One B-rep face of a CAD part: STEP entity #140.
In plain terms, the planar face has unit normal (0, -1, 0).
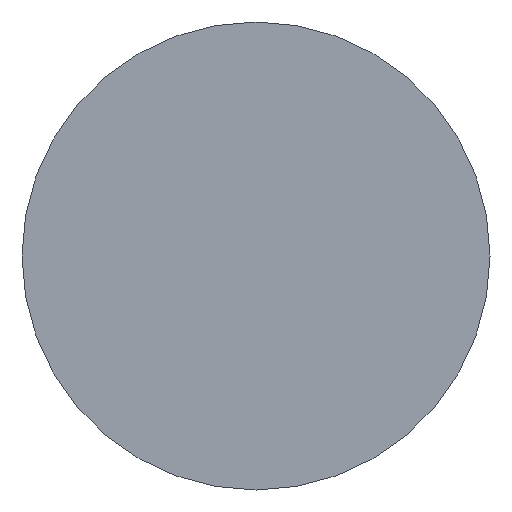
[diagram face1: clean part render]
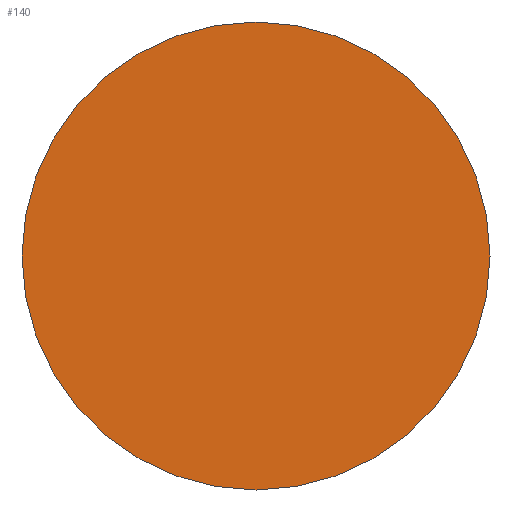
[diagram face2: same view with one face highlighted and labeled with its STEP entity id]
Its self-contained STEP definition (entity closure, numbers rounded to 3 decimals):
#31 = CYLINDRICAL_SURFACE('',#32,19.6);
#32 = AXIS2_PLACEMENT_3D('',#33,#34,#35);
#33 = CARTESIAN_POINT('',(31.,-33.5,43.));
#34 = DIRECTION('',(0.,1.,0.));
#35 = DIRECTION('',(0.,-0.,1.));
#56 = VERTEX_POINT('',#57);
#57 = CARTESIAN_POINT('',(31.,-33.5,62.6));
#78 = EDGE_CURVE('',#56,#56,#79,.T.);
#79 = SURFACE_CURVE('',#80,(#85,#92),.PCURVE_S1.);
#80 = CIRCLE('',#81,19.6);
#81 = AXIS2_PLACEMENT_3D('',#82,#83,#84);
#82 = CARTESIAN_POINT('',(31.,-33.5,43.));
#83 = DIRECTION('',(0.,1.,0.));
#84 = DIRECTION('',(0.,-0.,1.));
#85 = PCURVE('',#31,#86);
#86 = DEFINITIONAL_REPRESENTATION('',(#87),#91);
#87 = LINE('',#88,#89);
#88 = CARTESIAN_POINT('',(0.,0.));
#89 = VECTOR('',#90,1.);
#90 = DIRECTION('',(1.,0.));
#91 = ( GEOMETRIC_REPRESENTATION_CONTEXT(2) 
PARAMETRIC_REPRESENTATION_CONTEXT() REPRESENTATION_CONTEXT('2D SPACE',''
  ) );
#92 = PCURVE('',#93,#98);
#93 = PLANE('',#94);
#94 = AXIS2_PLACEMENT_3D('',#95,#96,#97);
#95 = CARTESIAN_POINT('',(31.,-33.5,43.));
#96 = DIRECTION('',(0.,1.,0.));
#97 = DIRECTION('',(0.,-0.,1.));
#98 = DEFINITIONAL_REPRESENTATION('',(#99),#103);
#99 = CIRCLE('',#100,19.6);
#100 = AXIS2_PLACEMENT_2D('',#101,#102);
#101 = CARTESIAN_POINT('',(0.,0.));
#102 = DIRECTION('',(1.,0.));
#103 = ( GEOMETRIC_REPRESENTATION_CONTEXT(2) 
PARAMETRIC_REPRESENTATION_CONTEXT() REPRESENTATION_CONTEXT('2D SPACE',''
  ) );
#140 = ADVANCED_FACE('',(#141),#93,.F.);
#141 = FACE_BOUND('',#142,.T.);
#142 = EDGE_LOOP('',(#143));
#143 = ORIENTED_EDGE('',*,*,#78,.F.);
